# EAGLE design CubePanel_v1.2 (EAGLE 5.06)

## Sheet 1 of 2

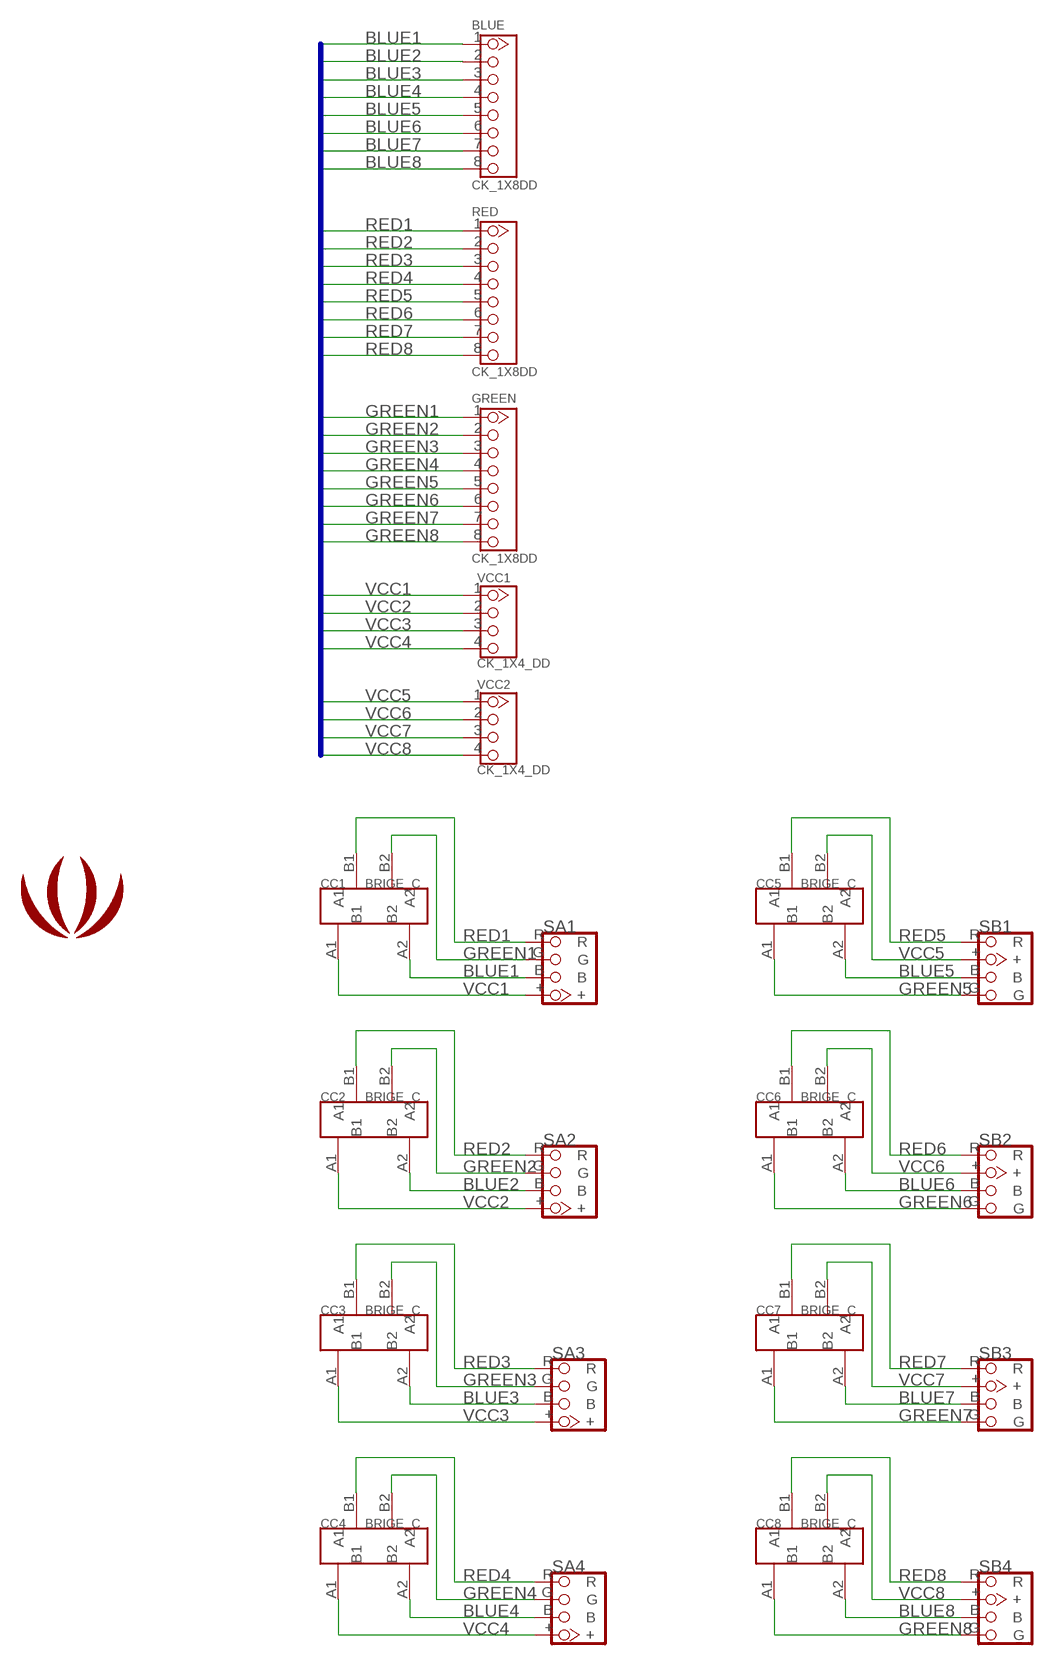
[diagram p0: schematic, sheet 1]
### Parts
BLUE  CK_1X8DD  [CK_1X8]
CC1  BRIGE_C  [BRIGE_C]
CC2  BRIGE_C  [BRIGE_C]
CC3  BRIGE_C  [BRIGE_C]
CC4  BRIGE_C  [BRIGE_C]
CC5  BRIGE_C  [BRIGE_C]
CC6  BRIGE_C  [BRIGE_C]
CC7  BRIGE_C  [BRIGE_C]
CC8  BRIGE_C  [BRIGE_C]
GREEN  CK_1X8DD  [CK_1X8]
LOGO1  LOGO_SILK  [LOGO_SILK]
RED  CK_1X8DD  [CK_1X8]
SA1  SIDE_A  [SIDE_A]
SA2  SIDE_A  [SIDE_A]
SA3  SIDE_A  [SIDE_A]
SA4  SIDE_A  [SIDE_A]
SB1  SIDE_B  [SIDE_B]
SB2  SIDE_B  [SIDE_B]
SB3  SIDE_B  [SIDE_B]
SB4  SIDE_B  [SIDE_B]
VCC1  CK_1X4_DD  [CK_1X4]
VCC2  CK_1X4_DD  [CK_1X4]

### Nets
BLUE1: BLUE.1 CC1.A2 SA1.B
BLUE2: BLUE.2 CC2.A2 SA2.B
BLUE3: BLUE.3 CC3.A2 SA3.B
BLUE4: BLUE.4 CC4.A2 SA4.B
BLUE5: BLUE.5 CC5.A2 SB1.B
BLUE6: BLUE.6 CC6.A2 SB2.B
BLUE7: BLUE.7 CC7.A2 SB3.B
BLUE8: BLUE.8 CC8.A2 SB4.B
GREEN1: CC1.B2 GREEN.1 SA1.G
GREEN2: CC2.B2 GREEN.2 SA2.G
GREEN3: CC3.B2 GREEN.3 SA3.G
GREEN4: CC4.B2 GREEN.4 SA4.G
GREEN5: CC5.A1 GREEN.5 SB1.G
GREEN6: CC6.A1 GREEN.6 SB2.G
GREEN7: CC7.A1 GREEN.7 SB3.G
GREEN8: CC8.A1 GREEN.8 SB4.G
RED1: CC1.B1 RED.1 SA1.R
RED2: CC2.B1 RED.2 SA2.R
RED3: CC3.B1 RED.3 SA3.R
RED4: CC4.B1 RED.4 SA4.R
RED5: CC5.B1 RED.5 SB1.R
RED6: CC6.B1 RED.6 SB2.R
RED7: CC7.B1 RED.7 SB3.R
RED8: CC8.B1 RED.8 SB4.R
VCC1: CC1.A1 SA1.+ VCC1.1
VCC2: CC2.A1 SA2.+ VCC1.2
VCC3: CC3.A1 SA3.+ VCC1.3
VCC4: CC4.A1 SA4.+ VCC1.4
VCC5: CC5.B2 SB1.+ VCC2.1
VCC6: CC6.B2 SB2.+ VCC2.2
VCC7: CC7.B2 SB3.+ VCC2.3
VCC8: CC8.B2 SB4.+ VCC2.4

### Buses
BLUE[1..8],RED[1..8],GREEN[1..8],VCC[1..8]

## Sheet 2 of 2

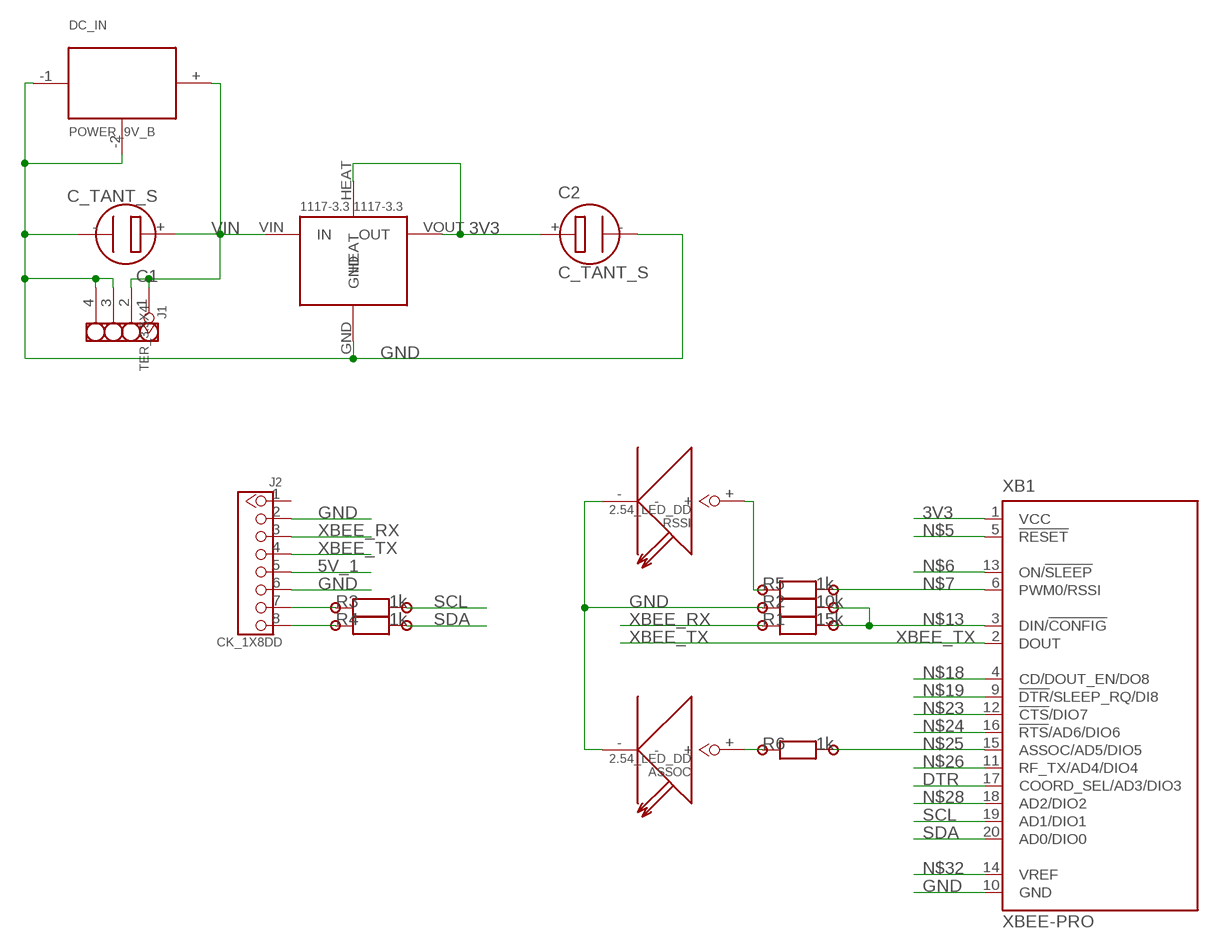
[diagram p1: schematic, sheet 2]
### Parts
1117-3.3  1117-3.3  LD1117TO220  [TO-220]
ASSOC  2.54_LED_DD  [2.54_LED]
C1  C_TANT_S  [C_TANT_S]
C2  C_TANT_S  [C_TANT_S]
DC_IN  POWER_9V_B  [POWER_9V_B]
J1  TER_3.5X4  [TER_3.5X4]
J2  CK_1X8DD  [CK_1X8]
R1  15k  R_350_25  [R_350_25]
R2  10k  R_350_25  [R_350_25]
R3  1k  R_350_25  [R_350_25]
R4  1k  R_350_25  [R_350_25]
R5  1k  R_350_25  [R_350_25]
R6  1k  R_350_25  [R_350_25]
RSSI  2.54_LED_DD  [2.54_LED]
XB1  XBEE-PRO  [XBEE-PRO]

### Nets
3V3: 1117-3.3.HEAT 1117-3.3.VOUT(OUT) C2.+ XB1.1(VCC)
5V_1: J2.5
DTR: XB1.17(COORD_SEL/AD3/DIO3)
GND: 1117-3.3.GND ASSOC.- C1.- C2.- DC_IN.-1 DC_IN.-2 J1.3 J1.4 J2.2 J2.6 R2.P$1 RSSI.- XB1.10(GND)
N$1: J2.7 R3.P$1
N$2: J2.8 R4.P$1
N$5: XB1.5(!RESET)
N$6: XB1.13(ON/!SLEEP)
N$7: R5.P$2 XB1.6(PWM0/RSSI)
N$13: R1.P$2 R2.P$2 XB1.3(DIN/!CONFIG)
N$18: XB1.4(CD/DOUT_EN/DO8)
N$19: XB1.9(!DTR!/SLEEP_RQ/DI8)
N$23: XB1.12(!CTS!/DIO7)
N$24: XB1.16(!RTS!/AD6/DIO6)
N$25: R6.P$2 XB1.15(ASSOC/AD5/DIO5)
N$26: XB1.11(RF_TX/AD4/DIO4)
N$28: XB1.18(AD2/DIO2)
N$32: XB1.14(VREF)
N$232: ASSOC.+ R6.P$1
N$239: R5.P$1 RSSI.+
SCL: R3.P$2 XB1.19(AD1/DIO1)
SDA: R4.P$2 XB1.20(AD0/DIO0)
VIN: 1117-3.3.VIN(IN) C1.+ DC_IN.+ J1.1 J1.2
XBEE_RX: J2.3 R1.P$1
XBEE_TX: J2.4 XB1.2(DOUT)
Unconnected: J2.1

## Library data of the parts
1117-3.3 = ICs_v54:LD1117
ASSOC RSSI = CPT_CJ:2.54_LED
BLUE GREEN J2 RED = CONNECTER:CK_1X8
C1 C2 = CPT_CJ:C_TANT_S
CC1-CC8 = CONNECTER:BRIGE
DC_IN = CONNECTER:POWER_9V_B
J1 = CONNECTER:TER_3.5X4
LOGO1 = logo:LOGO_SILK
R1-R6 = CPT_CJ:R_350_25
SA1-SA4 = Cube:SIDE_A
SB1-SB4 = Cube:SIDE_B
VCC1 VCC2 = CONNECTER:CK_1X4
XB1 = EXT_moudle:XBEE: XBee (TM) /XBee-PRO(TM) OEM RF Modules Source: MaxStream, Inc. xbee_productmanual.pdf

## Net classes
0 default: width 0.406 mm, drill 0.381 mm, clearance 0.254 mm
1 VCC1: width 0.813 mm, drill 0.381 mm, clearance 0.254 mm

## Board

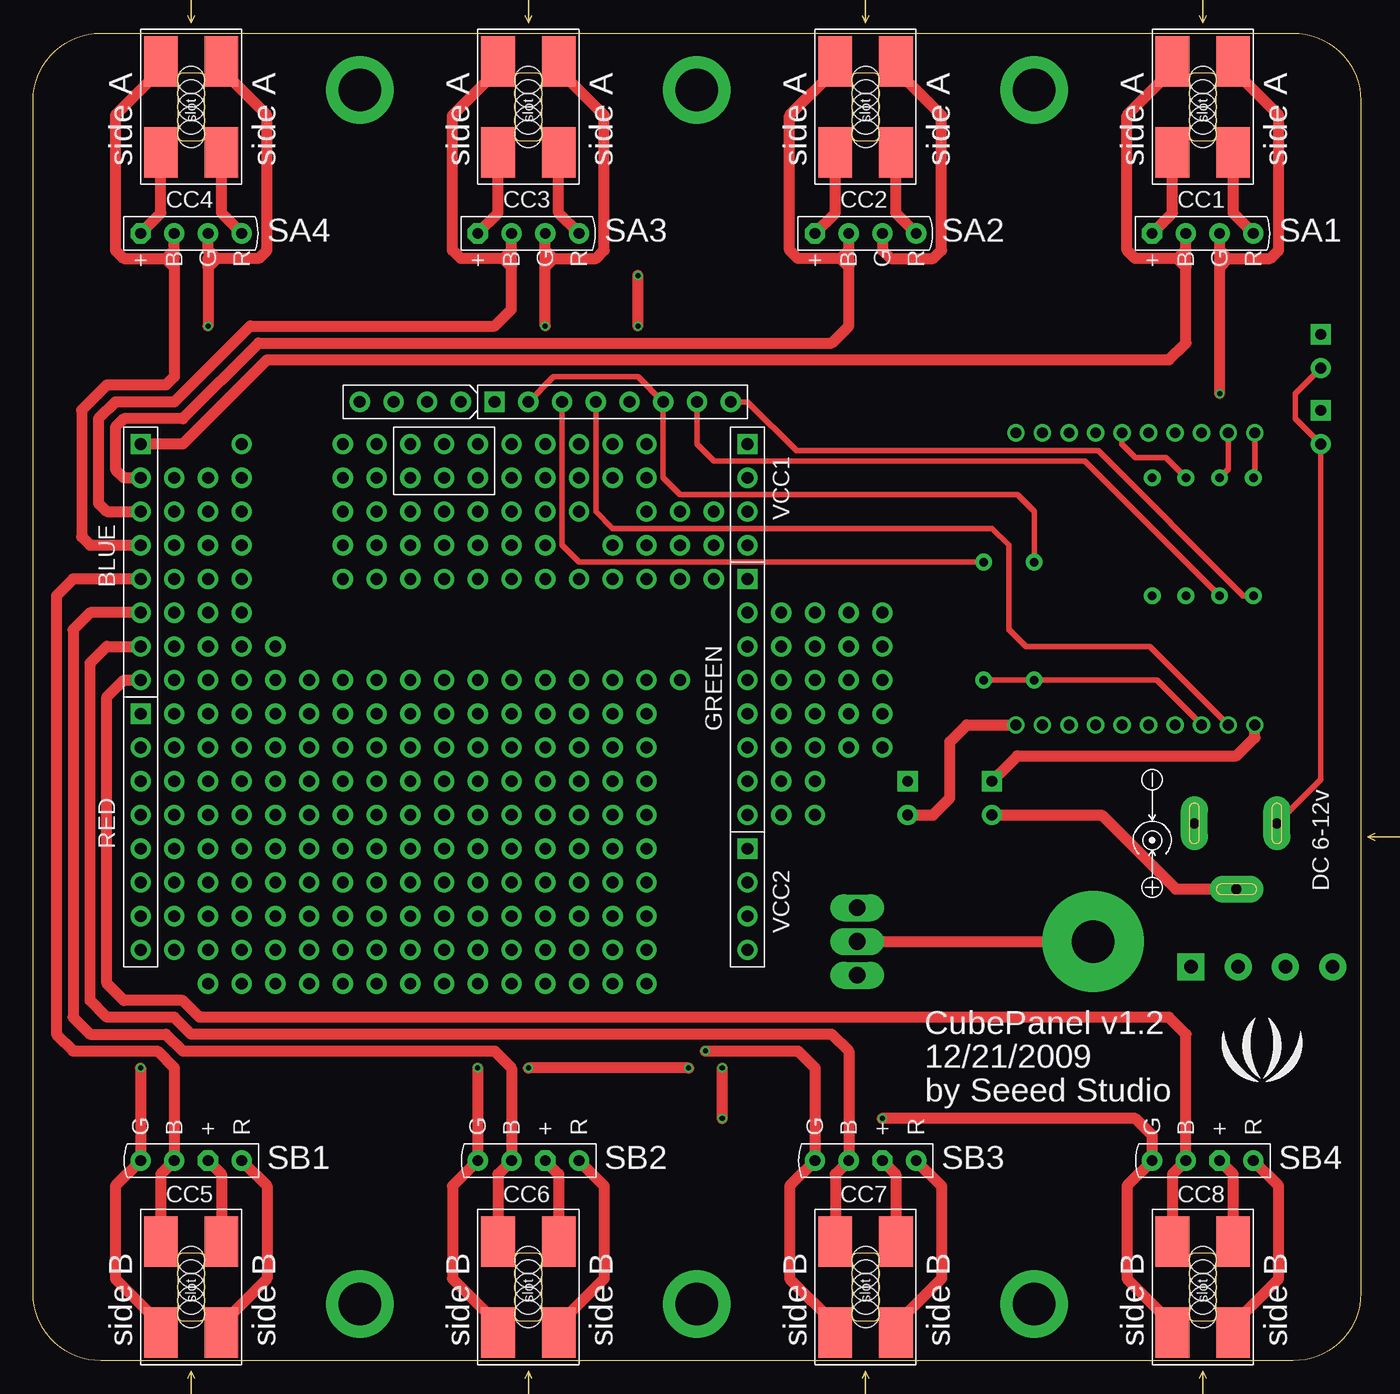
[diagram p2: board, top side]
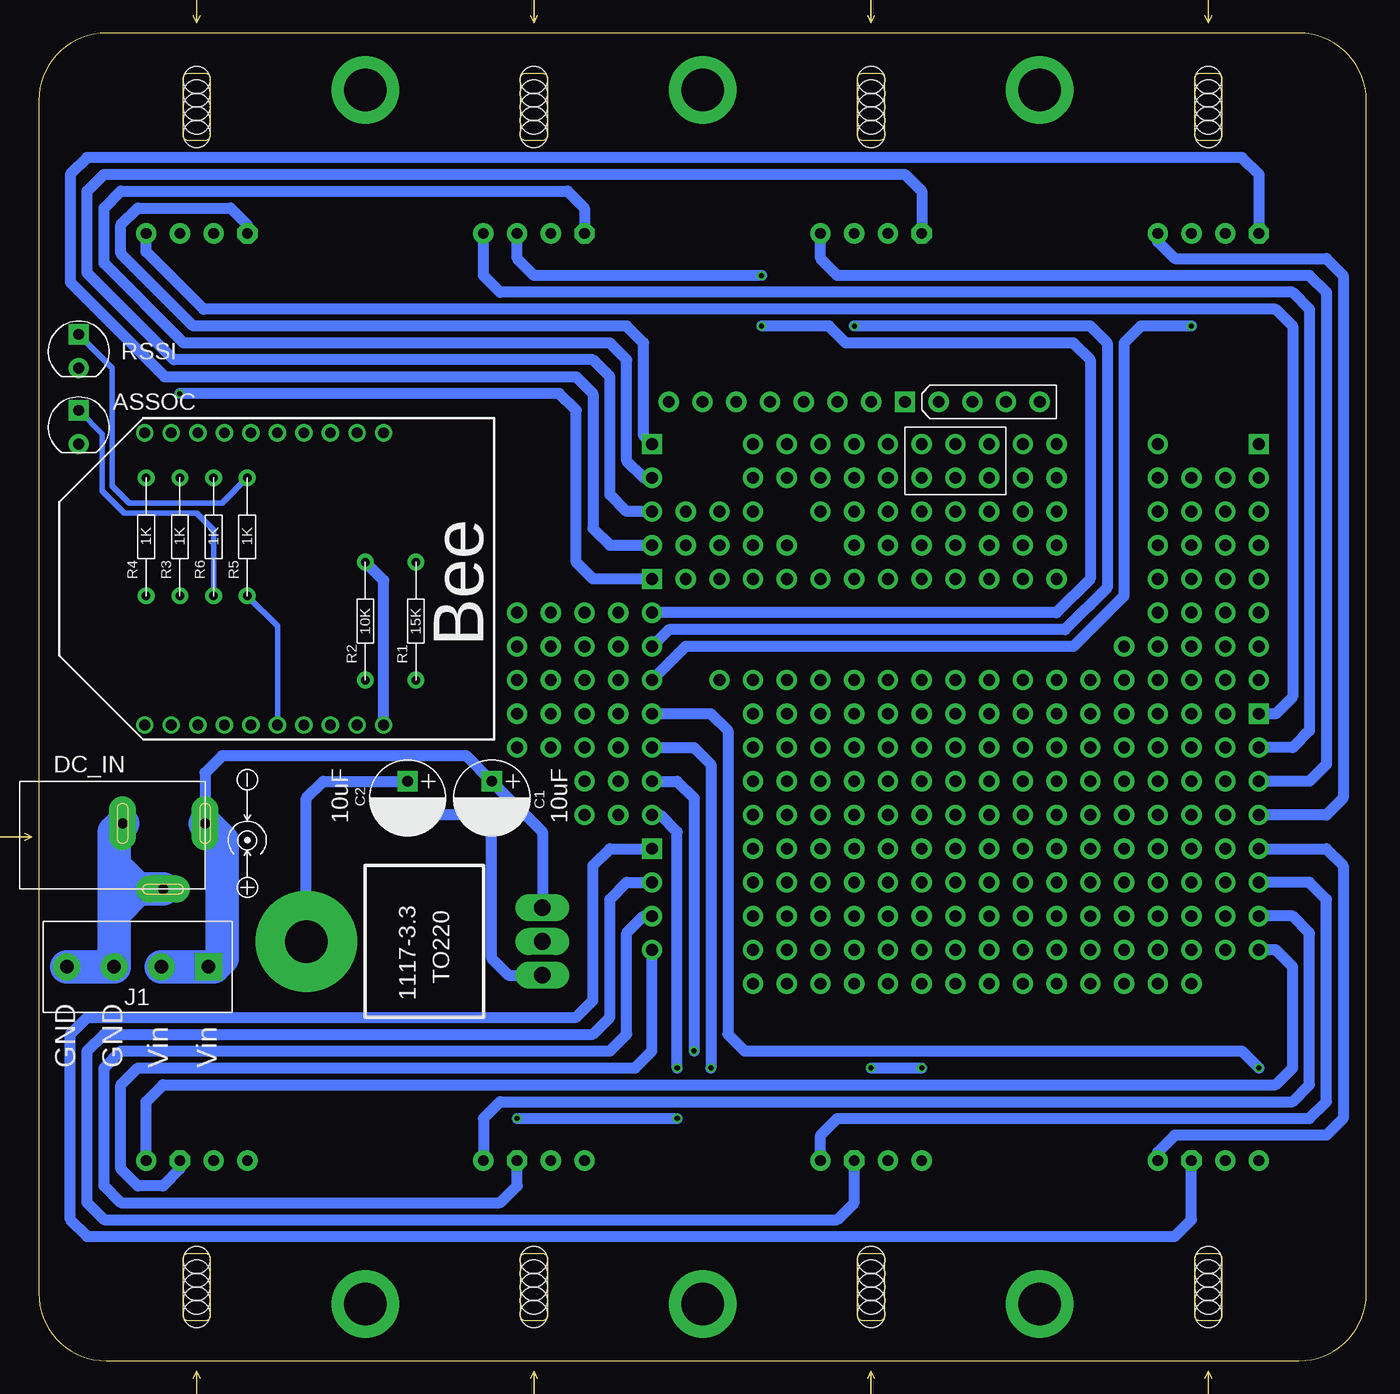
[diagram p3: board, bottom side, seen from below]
Size 100 x 100 mm. Coordinates in mm from the lower left corner, seen from the top.
Outline: 0,94.92 arc-90 5.08,100 94.92,100 arc-90 100,94.92 100,5.08 arc-90 94.92,0 5.08,0 arc-90 0,5.08 0,94.92
Copper layers (1*16): Top 0.035mm / dielectric 1.5mm / Bottom 0.035mm
Design rules "SeeedStudio_rule_no_angle_090911 *": minimum track width 6mil, minimum drill 12mil, track to track 6mil, track to pad 6mil, pad to pad 6mil, via to via 6mil, smd to smd 0mil, copper to edge 10mil, drill to drill 10mil, minimum pad ring 10mil, minimum via ring 6mil, stop-mask expansion 2mil, vias tented up to drill 25mil, thermal gap 10mil
Milling: 27 lines

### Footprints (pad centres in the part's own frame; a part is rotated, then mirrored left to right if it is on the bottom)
TO-220 = drill 1.27 pad 2.032 long: GND -2.54,-11.43; VIN 2.54,-11.43; VOUT 0,-11.43 | drill 3.2 pad 7.62 round: HEAT 0,6.35
2.54_LED = drill 0.813 pad 1.524 square: + -1.27,0 | drill 0.813 pad 1.524 round: - 1.27,0
CK_1X8 = drill 0.889 pad 1.524 square: 1 0,8.89 | drill 0.889 pad 1.524 round: 2 0,6.35; 3 0,3.81; 4 0,1.27; 5 0,-1.27; 6 0,-3.81; 7 0,-6.35; 8 0,-8.89
C_TANT_S = drill 0.813 pad 1.524 square: + -1.27,0 | drill 0.813 pad 1.524 round: - 1.27,0
BRIGE_C = smd 3.81 x 2.54: A1 -3.429,2.286; A2 3.429,2.286; B1 -3.429,-2.286; B2 3.429,-2.286 | hole 2.032: -2.032,0; 2.032,0; 0,0; -1.016,0; 1.016,0
POWER_9V_B = drill 0.762 pad 2.032 long: + 3.175,0; -1 -3.048,0; -2 0,-4.953
TER_3.5X4 = drill 1.016 pad 2.032 square: 1 0,5.334 | drill 1.016 pad 2.032 round: 2 0,1.778; 3 0,-1.778; 4 0,-5.334
R_350_25 = drill 0.635 pad 1.27 round: P$1 -4.445,0; P$2 4.445,0
SIDE_A = drill 0.813 pad 1.524 octagon: + -3.81,0 | drill 0.813 pad 1.524 round: B -1.27,0; G 1.27,0; R 3.81,0
SIDE_B = drill 0.813 pad 1.524 octagon: + -1.27,0 | drill 0.813 pad 1.524 round: B 1.27,0; G 3.81,0; R -3.81,0
CK_1X4 = drill 0.889 pad 1.524 square: 1 0,3.81 | drill 0.889 pad 1.524 round: 2 0,1.27; 3 0,-1.27; 4 0,-3.81
XBEE-PRO = drill 0.8 pad 1.27 round: 1 -11,9; 2 -11,7; 3 -11,5; 4 -11,3; 5 -11,1; 6 -11,-1; 7 -11,-3; 8 -11,-5; 9 -11,-7; 10 -11,-9; 11 11,-9; 12 11,-7; 13 11,-5; 14 11,-3; 15 11,-1; 16 11,1; 17 11,3; 18 11,5; 19 11,7; 20 11,9

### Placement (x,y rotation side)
1117-3.3  73.5,31.59 90 bottom
ASSOC  96.99,70.32 270 bottom
BLUE  8.09,60.16 0 top
C1  65.88,42.38 270 bottom
C2  72.22,42.38 270 bottom
CC1  88.1,94.45 90 top
CC2  62.7,94.45 90 top
CC3  37.3,94.45 90 top
CC4  11.9,94.45 90 top
CC5  11.9,5.55 90 top
CC6  37.3,5.55 90 top
CC7  62.7,5.55 90 top
CC8  88.1,5.55 90 top
DC_IN  90.64,40.48 0 bottom
GREEN  53.81,50 0 top
J1  92.55,29.68 270 bottom
J2  43.65,72.22 90 top
LOGO1  92.55,22.7 0 top
R1  71.59,55.72 270 bottom
R2  75.4,55.72 270 bottom
R3  89.37,62.06 90 bottom
R4  91.91,62.06 90 bottom
R5  84.29,62.06 270 bottom
R6  86.83,62.06 90 bottom
RED  8.09,39.84 0 top
RSSI  96.99,76.03 270 bottom
SA1  88.1,84.92 0 top
SA2  62.7,84.92 0 top
SA3  37.3,84.92 0 top
SA4  11.9,84.92 0 top
SB1  11.9,15.08 180 top
SB2  37.3,15.08 180 top
SB3  62.7,15.08 180 top
SB4  88.1,15.08 180 top
VCC1  53.81,65.24 0 top
VCC2  53.81,34.76 0 top
XB1  83.02,58.89 90 bottom

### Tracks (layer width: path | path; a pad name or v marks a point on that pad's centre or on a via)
3V3
  Top 0.813: C2.+ 74.13,45.55 90.64,45.55 92.02,46.94 XB1.1 | 1117-3.3.VOUT 1117-3.3.HEAT
  Bottom 0.813: 1117-3.3.HEAT 79.84,42.38 78.58,43.65 C2.+
BLUE1
  Top 0.813: 86.83,83.02 SA1.B | CC1.A2 85.81,97.24 82.38,93.81 82.38,83.66 83.02,83.02 86.19,83.02 | 86.83,83.02 86.83,83.66 86.19,83.02 | 86.83,83.02 86.19,83.02 | 86.83,83.02 86.83,82.38 86.19,83.02 | BLUE.1 11.27,69.05 17.62,75.4 85.56,75.4 86.83,76.67 86.83,83.02
BLUE2
  Top 0.813: 61.43,83.02 SA2.B | CC2.A2 60.41,97.24 56.98,93.81 56.98,83.66 57.62,83.02 60.8,83.02 | 61.43,83.02 61.43,83.66 60.8,83.02 | 61.43,83.02 60.8,83.02 | 61.43,83.02 61.43,82.38 60.8,83.02 | BLUE.2 6.82,66.51 6.19,67.14 6.19,70.32 6.82,70.95 11.27,70.95 16.98,76.67 60.16,76.67 61.43,77.94 61.43,83.02
BLUE3
  Top 0.813: 36.03,83.02 SA3.B | CC3.A2 35.01,97.24 31.59,93.81 31.59,83.66 32.22,83.02 35.39,83.02 | 35.39,83.02 36.03,82.38 36.03,83.02 | 36.03,83.02 35.39,83.02 | 35.39,83.02 36.03,83.66 36.03,83.02 | BLUE.3 5.55,63.97 4.91,64.61 4.91,70.95 6.19,72.22 10.63,72.22 16.34,77.94 34.76,77.94 36.03,79.21 36.03,83.02
BLUE4
  Top 0.813: 10.63,83.02 SA4.B | CC4.A2 9.61,97.24 6.19,93.81 6.19,83.66 6.82,83.02 9.99,83.02 | 9.99,83.02 10.63,82.38 | 10.63,82.38 10.63,83.02 | 9.99,83.02 10.63,83.02 | 9.99,83.02 10.63,83.66 10.63,83.02 | BLUE.4 4.28,61.43 3.65,62.06 3.65,71.59 5.55,73.5 9.99,73.5 10.63,74.13 10.63,82.38
BLUE5
  Top 0.813: CC5.A2 9.61,14.06 SB1.B 10.63,22.06 9.36,23.33 3.01,23.33 1.74,24.6 1.74,57.62 3.01,58.89 BLUE.5
BLUE6
  Top 0.813: CC6.A2 35.01,14.06 SB2.B 36.03,22.06 34.76,23.33 11.27,23.33 9.99,24.6 4.28,24.6 3.01,25.87 3.01,55.08 4.28,56.35 BLUE.6
BLUE7
  Top 0.813: CC7.A2 60.41,14.06 SB3.B 61.43,23.33 60.16,24.6 11.9,24.6 10.63,25.87 5.55,25.87 4.28,27.14 4.28,52.54 5.55,53.81 BLUE.7
BLUE8
  Top 0.813: CC8.A2 85.81,14.06 SB4.B 86.83,24.6 85.56,25.87 12.53,25.87 11.27,27.14 6.82,27.14 5.55,28.41 5.55,50 6.82,51.27 BLUE.8
GND
  Top 0.406: J2.2 39.2,74.13 45.55,74.13 J2.6 47.46,66.51 48.73,65.24 74.13,65.24 75.4,63.97 R2.P$1 | DC_IN.-1 96.99,43.78 ASSOC.- 95.09,70.95 95.09,72.86 RSSI.-
  Top 0.813: XB1.10 70.32,47.89 69.05,46.62 69.05,42.38 67.78,41.11 C1.- | C2.- 80.48,41.11 86.07,35.52 DC_IN.-2
  Bottom 0.813: C2.- C1.- 65.88,30.32 64.61,29.05 1117-3.3.GND | XB1.10 74.02,58.78 R2.P$1
  Bottom 2.54: J1.4 J1.3 94.32,35.52 | 94.32,35.52 94.32,39.84 DC_IN.-1 | DC_IN.-2 92.55,35.52 | 92.55,35.52 94.32,33.74 | 94.32,33.74 94.32,32.73 | 94.32,33.74 94.32,35.52 | 92.55,35.52 94.32,35.52 | 92.55,35.52 92.16,35.52 | 92.55,35.52 94.32,37.3 94.32,35.52
  pour Top: -15.41,81.75 -14.14,81.75 -14.14,80.48 -15.41,80.48
GREEN1  (via drill 0.38)
  Top 0.813: CC1.B2 90.39,97.24 93.81,93.81 93.81,83.66 93.18,83.02 90,83.02 | 90,83.02 89.37,83.02 89.37,82.38 90,83.02 | 89.37,83.66 90,83.02 | 89.37,83.66 SA1.G | v89.37,72.86 89.37,83.66
  Bottom 0.813: GREEN.1 58.26,58.89 59.52,60.16 59.52,71.59 60.8,72.86 v89.37,72.86
GREEN2  (via drill 0.38)
  Top 0.813: CC2.B2 64.99,97.24 68.41,93.81 68.41,83.66 67.78,83.02 64.61,83.02 63.97,83.66 SA2.G | v45.55,77.94 v45.55,81.75
  Bottom 0.813: v45.55,77.94 40.48,77.94 39.2,76.67 22.06,76.67 20.79,75.4 20.79,58.89 23.33,56.35 GREEN.2 | v45.55,81.75 62.7,81.75 63.97,83.02 SA2.G
GREEN3  (via drill 0.38)
  Top 0.813: CC3.B2 39.59,97.24 43.02,93.81 43.02,83.66 42.38,83.02 39.2,83.02 | 39.2,83.02 38.57,83.02 38.57,82.38 39.2,83.02 | 38.57,83.66 39.2,83.02 | 38.57,83.66 SA3.G | v38.57,77.94 38.57,83.66
  Bottom 0.813: v38.57,77.94 20.79,77.94 19.52,76.67 19.52,58.26 22.7,55.08 52.54,55.08 GREEN.3
GREEN4  (via drill 0.38)
  Top 0.813: CC4.B2 14.19,97.24 17.62,93.81 17.62,83.66 16.98,83.02 13.8,83.02 | 13.8,83.02 13.17,82.38 | 13.17,82.38 13.17,83.02 13.8,83.02 | 13.8,83.02 13.17,83.66 SA4.G | 13.17,82.38 v13.17,77.94
  Bottom 0.813: v13.17,77.94 16.98,77.94 18.25,76.67 18.25,57.62 22.06,53.81 51.27,53.81 GREEN.4
GREEN5  (via drill 0.38)
  Top 0.813: CC5.A1 9.61,2.76 6.19,6.19 6.19,13.17 SB1.G v8.09,22.06
  Bottom 0.813: GREEN.5 49.37,48.73 48.09,47.46 48.09,24.6 46.83,23.33 9.36,23.33 v8.09,22.06
GREEN6  (via drill 0.38)
  Top 0.813: CC6.A1 35.01,2.76 31.59,6.19 31.59,13.17 SB2.G v33.49,22.06 | v49.37,22.06 v37.3,22.06
  Bottom 0.813: GREEN.6 50.63,46.19 49.37,44.92 v49.37,22.06 | v37.3,22.06 v33.49,22.06
GREEN7  (via drill 0.38)
  Top 0.813: CC7.A1 60.41,2.76 56.98,6.19 56.98,13.17 SB3.G 58.89,22.06 57.62,23.33 v50.63,23.33
  Bottom 0.813: GREEN.7 51.91,43.65 50.63,42.38 v50.63,23.33
GREEN8  (via drill 0.38)
  Top 0.813: CC8.A1 85.81,2.76 82.38,6.19 82.38,13.17 SB4.G 84.29,16.98 83.02,18.25 v63.97,18.25 | v51.91,18.25 v51.91,22.06
  Bottom 0.813: v63.97,18.25 v51.91,18.25 | v51.91,22.06 51.91,39.84 53.17,41.11 GREEN.8
N$1
  Top 0.406: J2.7 50,69.05 51.27,67.78 79.21,67.78 R3.P$1
N$2
  Top 0.406: J2.8 53.81,72.22 57.49,68.54 80.23,68.54 91.15,57.62 R4.P$1
N$3  (via drill 0.89 pad 1.52)
  other vias: 10.63,66.51
N$4  (via drill 0.89 pad 1.52)
  other vias: 13.17,66.51
N$7
  Bottom 0.406: XB1.6 82.02,55.35 R5.P$2
N$13
  Top 0.406: R1.P$2 R2.P$2 84.64,51.27 XB1.3
N$15  (via drill 0.89 pad 1.52)
  other vias: 15.71,66.51
N$25
  Top 0.406: XB1.15 82.02,69.03 83.02,68.03 85.31,68.03 R6.P$2
N$27  (via drill 0.89 pad 1.52)
  other vias: 24.6,72.22
N$29  (via drill 0.89 pad 1.52)
  other vias: 27.14,72.22
N$31  (via drill 0.89 pad 1.52)
  other vias: 29.68,72.22
N$33  (via drill 0.89 pad 1.52)
  other vias: 32.22,72.22
N$35  (via drill 0.89 pad 1.52)
  other vias: 30.95,69.05
N$36  (via drill 0.89 pad 1.52)
  other vias: 28.41,69.05
N$37  (via drill 0.89 pad 1.52)
  other vias: 28.41,66.51
N$38  (via drill 0.89 pad 1.52)
  other vias: 30.95,66.51
N$39  (via drill 0.89 pad 1.52)
  other vias: 15.71,63.97
N$40  (via drill 0.89 pad 1.52)
  other vias: 13.17,63.97
N$41  (via drill 0.89 pad 1.52)
  other vias: 10.63,63.97
N$42  (via drill 0.89 pad 1.52)
  other vias: 10.63,61.43
N$43  (via drill 0.89 pad 1.52)
  other vias: 13.17,61.43
N$44  (via drill 0.89 pad 1.52)
  other vias: 15.71,61.43
N$45  (via drill 0.89 pad 1.52)
  other vias: 25.87,69.05
N$47  (via drill 0.89 pad 1.52)
  other vias: 23.33,69.05
N$48  (via drill 0.89 pad 1.52)
  other vias: 23.33,66.51
N$49  (via drill 0.89 pad 1.52)
  other vias: 25.87,66.51
N$50  (via drill 0.89 pad 1.52)
  other vias: 10.63,58.89
N$52  (via drill 0.89 pad 1.52)
  other vias: 13.17,58.89
N$53  (via drill 0.89 pad 1.52)
  other vias: 15.71,58.89
N$54  (via drill 0.89 pad 1.52)
  other vias: 25.87,63.97
N$55  (via drill 0.89 pad 1.52)
  other vias: 23.33,63.97
N$56  (via drill 0.89 pad 1.52)
  other vias: 28.41,63.97
N$57  (via drill 0.89 pad 1.52)
  other vias: 30.95,63.97
N$58  (via drill 0.89 pad 1.52)
  other vias: 30.95,61.43
N$59  (via drill 0.89 pad 1.52)
  other vias: 28.41,61.43
N$60  (via drill 0.89 pad 1.52)
  other vias: 25.87,61.43
N$61  (via drill 0.89 pad 1.52)
  other vias: 23.33,61.43
N$62  (via drill 0.89 pad 1.52)
  other vias: 15.71,56.35
N$63  (via drill 0.89 pad 1.52)
  other vias: 13.17,56.35
N$64  (via drill 0.89 pad 1.52)
  other vias: 10.63,56.35
N$65  (via drill 0.89 pad 1.52)
  other vias: 10.63,53.81
N$66  (via drill 0.89 pad 1.52)
  other vias: 13.17,53.81
N$67  (via drill 0.89 pad 1.52)
  other vias: 15.71,53.81
N$68  (via drill 0.89 pad 1.52)
  other vias: 23.33,58.89
N$69  (via drill 0.89 pad 1.52)
  other vias: 25.87,58.89
N$70  (via drill 0.89 pad 1.52)
  other vias: 28.41,58.89
N$71  (via drill 0.89 pad 1.52)
  other vias: 30.95,58.89
N$72  (via drill 0.89 pad 1.52)
  other vias: 38.57,69.05
N$73  (via drill 0.89 pad 1.52)
  other vias: 38.57,66.51
N$74  (via drill 0.89 pad 1.52)
  other vias: 38.57,63.97
N$75  (via drill 0.89 pad 1.52)
  other vias: 38.57,61.43
N$76  (via drill 0.89 pad 1.52)
  other vias: 15.71,51.27
N$77  (via drill 0.89 pad 1.52)
  other vias: 13.17,51.27
N$78  (via drill 0.89 pad 1.52)
  other vias: 10.63,51.27
N$79  (via drill 0.89 pad 1.52)
  other vias: 10.63,48.73
N$80  (via drill 0.89 pad 1.52)
  other vias: 13.17,48.73
N$81  (via drill 0.89 pad 1.52)
  other vias: 15.71,48.73
N$82  (via drill 0.89 pad 1.52)
  other vias: 18.25,48.73
N$83  (via drill 0.89 pad 1.52)
  other vias: 20.79,48.73
N$84  (via drill 0.89 pad 1.52)
  other vias: 23.33,48.73
N$85  (via drill 0.89 pad 1.52)
  other vias: 25.87,48.73
N$86  (via drill 0.89 pad 1.52)
  other vias: 25.87,46.19
N$87  (via drill 0.89 pad 1.52)
  other vias: 23.33,46.19
N$88  (via drill 0.89 pad 1.52)
  other vias: 20.79,46.19
N$89  (via drill 0.89 pad 1.52)
  other vias: 18.25,46.19
N$90  (via drill 0.89 pad 1.52)
  other vias: 15.71,46.19
N$91  (via drill 0.89 pad 1.52)
  other vias: 13.17,46.19
N$92  (via drill 0.89 pad 1.52)
  other vias: 10.63,46.19
N$93  (via drill 0.89 pad 1.52)
  other vias: 10.63,43.65
N$94  (via drill 0.89 pad 1.52)
  other vias: 13.17,43.65
N$95  (via drill 0.89 pad 1.52)
  other vias: 15.71,43.65
N$96  (via drill 0.89 pad 1.52)
  other vias: 18.25,43.65
N$97  (via drill 0.89 pad 1.52)
  other vias: 20.79,43.65
N$98  (via drill 0.89 pad 1.52)
  other vias: 23.33,43.65
N$99  (via drill 0.89 pad 1.52)
  other vias: 25.87,43.65
N$100  (via drill 0.89 pad 1.52)
  other vias: 28.41,48.73
N$101  (via drill 0.89 pad 1.52)
  other vias: 30.95,48.73
N$102  (via drill 0.89 pad 1.52)
  other vias: 33.49,48.73
N$103  (via drill 0.89 pad 1.52)
  other vias: 36.03,48.73
N$104  (via drill 0.89 pad 1.52)
  other vias: 38.57,48.73
N$105  (via drill 0.89 pad 1.52)
  other vias: 41.11,48.73
N$106  (via drill 0.89 pad 1.52)
  other vias: 43.65,48.73
N$107  (via drill 0.89 pad 1.52)
  other vias: 46.19,48.73
N$108  (via drill 0.89 pad 1.52)
  other vias: 46.19,46.19
N$109  (via drill 0.89 pad 1.52)
  other vias: 43.65,46.19
N$110  (via drill 0.89 pad 1.52)
  other vias: 41.11,46.19
N$111  (via drill 0.89 pad 1.52)
  other vias: 38.57,46.19
N$112  (via drill 0.89 pad 1.52)
  other vias: 36.03,46.19
N$113  (via drill 0.89 pad 1.52)
  other vias: 33.49,46.19
N$114  (via drill 0.89 pad 1.52)
  other vias: 30.95,46.19
N$115  (via drill 0.89 pad 1.52)
  other vias: 28.41,46.19
N$116  (via drill 0.89 pad 1.52)
  other vias: 28.41,43.65
N$117  (via drill 0.89 pad 1.52)
  other vias: 30.95,43.65
N$118  (via drill 0.89 pad 1.52)
  other vias: 33.49,43.65
N$119  (via drill 0.89 pad 1.52)
  other vias: 36.03,43.65
N$120  (via drill 0.89 pad 1.52)
  other vias: 38.57,43.65
N$121  (via drill 0.89 pad 1.52)
  other vias: 41.11,43.65
N$122  (via drill 0.89 pad 1.52)
  other vias: 43.65,43.65
N$123  (via drill 0.89 pad 1.52)
  other vias: 46.19,43.65
N$124  (via drill 0.89 pad 1.52)
  other vias: 46.19,41.11
N$125  (via drill 0.89 pad 1.52)
  other vias: 43.65,41.11
N$126  (via drill 0.89 pad 1.52)
  other vias: 41.11,41.11
N$127  (via drill 0.89 pad 1.52)
  other vias: 38.57,41.11
N$128  (via drill 0.89 pad 1.52)
  other vias: 36.03,41.11
N$129  (via drill 0.89 pad 1.52)
  other vias: 33.49,41.11
N$130  (via drill 0.89 pad 1.52)
  other vias: 30.95,41.11
N$131  (via drill 0.89 pad 1.52)
  other vias: 28.41,41.11
N$132  (via drill 0.89 pad 1.52)
  other vias: 25.87,41.11
N$133  (via drill 0.89 pad 1.52)
  other vias: 23.33,41.11
N$134  (via drill 0.89 pad 1.52)
  other vias: 20.79,41.11
N$135  (via drill 0.89 pad 1.52)
  other vias: 18.25,41.11
N$136  (via drill 0.89 pad 1.52)
  other vias: 15.71,41.11
N$137  (via drill 0.89 pad 1.52)
  other vias: 13.17,41.11
N$138  (via drill 0.89 pad 1.52)
  other vias: 10.63,41.11
N$139  (via drill 0.89 pad 1.52)
  other vias: 10.63,38.57
N$140  (via drill 0.89 pad 1.52)
  other vias: 13.17,38.57
N$141  (via drill 0.89 pad 1.52)
  other vias: 15.71,38.57
N$142  (via drill 0.89 pad 1.52)
  other vias: 18.25,38.57
N$143  (via drill 0.89 pad 1.52)
  other vias: 20.79,38.57
N$144  (via drill 0.89 pad 1.52)
  other vias: 23.33,38.57
N$145  (via drill 0.89 pad 1.52)
  other vias: 25.87,38.57
N$146  (via drill 0.89 pad 1.52)
  other vias: 28.41,38.57
N$147  (via drill 0.89 pad 1.52)
  other vias: 30.95,38.57
N$148  (via drill 0.89 pad 1.52)
  other vias: 33.49,38.57
N$149  (via drill 0.89 pad 1.52)
  other vias: 36.03,38.57
N$150  (via drill 0.89 pad 1.52)
  other vias: 38.57,38.57
N$151  (via drill 0.89 pad 1.52)
  other vias: 41.11,38.57
N$152  (via drill 0.89 pad 1.52)
  other vias: 43.65,38.57
N$153  (via drill 0.89 pad 1.52)
  other vias: 46.19,38.57
N$154  (via drill 0.89 pad 1.52)
  other vias: 46.19,36.03
N$155  (via drill 0.89 pad 1.52)
  other vias: 43.65,36.03
N$156  (via drill 0.89 pad 1.52)
  other vias: 41.11,36.03
N$157  (via drill 0.89 pad 1.52)
  other vias: 38.57,36.03
N$158  (via drill 0.89 pad 1.52)
  other vias: 36.03,36.03
N$159  (via drill 0.89 pad 1.52)
  other vias: 33.49,36.03
N$160  (via drill 0.89 pad 1.52)
  other vias: 30.95,36.03
N$161  (via drill 0.89 pad 1.52)
  other vias: 28.41,36.03
N$162  (via drill 0.89 pad 1.52)
  other vias: 25.87,36.03
N$163  (via drill 0.89 pad 1.52)
  other vias: 23.33,36.03
N$164  (via drill 0.89 pad 1.52)
  other vias: 20.79,36.03
N$165  (via drill 0.89 pad 1.52)
  other vias: 18.25,36.03
N$166  (via drill 0.89 pad 1.52)
  other vias: 15.71,36.03
N$167  (via drill 0.89 pad 1.52)
  other vias: 13.17,36.03
N$168  (via drill 0.89 pad 1.52)
  other vias: 10.63,36.03
N$169  (via drill 0.89 pad 1.52)
  other vias: 10.63,33.49
N$170  (via drill 0.89 pad 1.52)
  other vias: 13.17,33.49
N$171  (via drill 0.89 pad 1.52)
  other vias: 15.71,33.49
N$172  (via drill 0.89 pad 1.52)
  other vias: 18.25,33.49
N$173  (via drill 0.89 pad 1.52)
  other vias: 20.79,33.49
N$174  (via drill 0.89 pad 1.52)
  other vias: 23.33,33.49
N$175  (via drill 0.89 pad 1.52)
  other vias: 25.87,33.49
N$176  (via drill 0.89 pad 1.52)
  other vias: 28.41,33.49
N$177  (via drill 0.89 pad 1.52)
  other vias: 30.95,33.49
N$178  (via drill 0.89 pad 1.52)
  other vias: 33.49,33.49
N$179  (via drill 0.89 pad 1.52)
  other vias: 36.03,33.49
N$180  (via drill 0.89 pad 1.52)
  other vias: 38.57,33.49
N$181  (via drill 0.89 pad 1.52)
  other vias: 41.11,33.49
N$182  (via drill 0.89 pad 1.52)
  other vias: 43.65,33.49
N$183  (via drill 0.89 pad 1.52)
  other vias: 46.19,33.49
N$184  (via drill 0.89 pad 1.52)
  other vias: 46.19,30.95
N$185  (via drill 0.89 pad 1.52)
  other vias: 43.65,30.95
N$186  (via drill 0.89 pad 1.52)
  other vias: 41.11,30.95
N$187  (via drill 0.89 pad 1.52)
  other vias: 38.57,30.95
N$188  (via drill 0.89 pad 1.52)
  other vias: 36.03,30.95
N$189  (via drill 0.89 pad 1.52)
  other vias: 33.49,30.95
N$190  (via drill 0.89 pad 1.52)
  other vias: 30.95,30.95
N$191  (via drill 0.89 pad 1.52)
  other vias: 28.41,30.95
N$192  (via drill 0.89 pad 1.52)
  other vias: 25.87,30.95
N$193  (via drill 0.89 pad 1.52)
  other vias: 23.33,30.95
N$194  (via drill 0.89 pad 1.52)
  other vias: 20.79,30.95
N$195  (via drill 0.89 pad 1.52)
  other vias: 18.25,30.95
N$196  (via drill 0.89 pad 1.52)
  other vias: 15.71,30.95
N$197  (via drill 0.89 pad 1.52)
  other vias: 13.17,30.95
N$198  (via drill 0.89 pad 1.52)
  other vias: 10.63,30.95
N$199  (via drill 0.89 pad 1.52)
  other vias: 41.11,28.41
N$200  (via drill 0.89 pad 1.52)
  other vias: 43.65,28.41
N$201  (via drill 0.89 pad 1.52)
  other vias: 46.19,28.41
N$202  (via drill 0.89 pad 1.52)
  other vias: 33.49,58.89
N$203  (via drill 0.89 pad 1.52)
  other vias: 33.49,61.43
N$204  (via drill 0.89 pad 1.52)
  other vias: 33.49,63.97
N$205  (via drill 0.89 pad 1.52)
  other vias: 33.49,66.51
N$206  (via drill 0.89 pad 1.52)
  other vias: 33.49,69.05
N$207  (via drill 0.89 pad 1.52)
  other vias: 36.03,69.05
N$208  (via drill 0.89 pad 1.52)
  other vias: 36.03,66.51
N$209  (via drill 0.89 pad 1.52)
  other vias: 36.03,63.97
N$210  (via drill 0.89 pad 1.52)
  other vias: 36.03,61.43
N$211  (via drill 0.89 pad 1.52)
  other vias: 36.03,58.89
N$212  (via drill 0.89 pad 1.52)
  other vias: 56.35,56.35
N$213  (via drill 0.89 pad 1.52)
  other vias: 58.89,56.35
N$214  (via drill 0.89 pad 1.52)
  other vias: 61.43,56.35
N$215  (via drill 0.89 pad 1.52)
  other vias: 63.97,56.35
N$216  (via drill 0.89 pad 1.52)
  other vias: 63.97,53.81
N$217  (via drill 0.89 pad 1.52)
  other vias: 61.43,53.81
N$218  (via drill 0.89 pad 1.52)
  other vias: 58.89,53.81
N$219  (via drill 0.89 pad 1.52)
  other vias: 56.35,53.81
N$220  (via drill 0.89 pad 1.52)
  other vias: 56.35,51.27
N$221  (via drill 0.89 pad 1.52)
  other vias: 58.89,51.27
N$222  (via drill 0.89 pad 1.52)
  other vias: 61.43,51.27
N$223  (via drill 0.89 pad 1.52)
  other vias: 63.97,51.27
N$224  (via drill 0.89 pad 1.52)
  other vias: 63.97,48.73
N$225  (via drill 0.89 pad 1.52)
  other vias: 61.43,48.73
N$226  (via drill 0.89 pad 1.52)
  other vias: 58.89,48.73
N$227  (via drill 0.89 pad 1.52)
  other vias: 56.35,48.73
N$228  (via drill 0.89 pad 1.52)
  other vias: 56.35,46.19
N$229  (via drill 0.89 pad 1.52)
  other vias: 58.89,46.19
N$230  (via drill 0.89 pad 1.52)
  other vias: 61.43,46.19
N$231  (via drill 0.89 pad 1.52)
  other vias: 63.97,46.19
N$232
  Bottom 0.406: R6.P$1 86.83,62.57 88.1,63.84 93.56,63.84 95.21,65.49 95.21,69.81 ASSOC.+
N$233  (via drill 0.89 pad 1.52)
  other vias: 58.89,43.65
N$234  (via drill 0.89 pad 1.52)
  other vias: 56.35,43.65
N$235  (via drill 0.89 pad 1.52)
  other vias: 56.35,41.11
N$236  (via drill 0.89 pad 1.52)
  other vias: 58.89,41.11
N$237  (via drill 0.89 pad 1.52)
  other vias: 15.71,69.05
N$238  (via drill 0.89 pad 1.52)
  other vias: 18.25,53.81
N$239
  Bottom 0.406: R5.P$1 86.19,64.61 93.18,64.61 94.45,65.88 94.45,74.77 RSSI.+
N$243  (via drill 0.89 pad 1.52)
  other vias: 38.57,58.89
N$244  (via drill 3.2 pad 5.08)
  other vias: 24.6,95.72
N$245  (via drill 3.2 pad 5.08)
  other vias: 50,95.72
N$246  (via drill 3.2 pad 5.08)
  other vias: 75.4,95.72
N$247  (via drill 3.2 pad 5.08)
  other vias: 24.6,4.28
N$248  (via drill 3.2 pad 5.08)
  other vias: 50,4.28
N$249  (via drill 3.2 pad 5.08)
  other vias: 75.4,4.28
N$250  (via drill 0.89 pad 1.52)
  other vias: 41.11,58.89
N$251  (via drill 0.89 pad 1.52)
  other vias: 43.65,58.89
N$252  (via drill 0.89 pad 1.52)
  other vias: 46.19,58.89
N$253  (via drill 0.89 pad 1.52)
  other vias: 48.73,58.89
N$254  (via drill 0.89 pad 1.52)
  other vias: 51.27,58.89
N$255  (via drill 0.89 pad 1.52)
  other vias: 41.11,69.05
N$256  (via drill 0.89 pad 1.52)
  other vias: 41.11,66.51
N$257  (via drill 0.89 pad 1.52)
  other vias: 41.11,63.97
N$258  (via drill 0.89 pad 1.52)
  other vias: 43.65,61.43
N$259  (via drill 0.89 pad 1.52)
  other vias: 46.19,61.43
N$260  (via drill 0.89 pad 1.52)
  other vias: 48.73,61.43
N$261  (via drill 0.89 pad 1.52)
  other vias: 51.27,61.43
N$262  (via drill 0.89 pad 1.52)
  other vias: 51.27,63.97
N$263  (via drill 0.89 pad 1.52)
  other vias: 48.73,63.97
N$264  (via drill 0.89 pad 1.52)
  other vias: 46.19,63.97
N$265  (via drill 0.89 pad 1.52)
  other vias: 46.19,66.51
N$266  (via drill 0.89 pad 1.52)
  other vias: 46.19,69.05
N$267  (via drill 0.89 pad 1.52)
  other vias: 43.65,69.05
N$268  (via drill 0.89 pad 1.52)
  other vias: 43.65,66.51
N$269  (via drill 0.89 pad 1.52)
  other vias: 18.25,51.27
N$270  (via drill 0.89 pad 1.52)
  other vias: 20.79,51.27
N$271  (via drill 0.89 pad 1.52)
  other vias: 23.33,51.27
N$272  (via drill 0.89 pad 1.52)
  other vias: 25.87,51.27
N$273  (via drill 0.89 pad 1.52)
  other vias: 28.41,51.27
N$274  (via drill 0.89 pad 1.52)
  other vias: 30.95,51.27
N$275  (via drill 0.89 pad 1.52)
  other vias: 33.49,51.27
N$276  (via drill 0.89 pad 1.52)
  other vias: 36.03,51.27
N$277  (via drill 0.89 pad 1.52)
  other vias: 38.57,51.27
N$278  (via drill 0.89 pad 1.52)
  other vias: 41.11,51.27
N$279  (via drill 0.89 pad 1.52)
  other vias: 43.65,51.27
N$280  (via drill 0.89 pad 1.52)
  other vias: 46.19,51.27
N$281  (via drill 0.89 pad 1.52)
  other vias: 48.73,51.27
N$282  (via drill 0.89 pad 1.52)
  other vias: 13.17,28.41
N$283  (via drill 0.89 pad 1.52)
  other vias: 15.71,28.41
N$284  (via drill 0.89 pad 1.52)
  other vias: 18.25,28.41
N$285  (via drill 0.89 pad 1.52)
  other vias: 20.79,28.41
N$286  (via drill 0.89 pad 1.52)
  other vias: 23.33,28.41
N$287  (via drill 0.89 pad 1.52)
  other vias: 25.87,28.41
N$288  (via drill 0.89 pad 1.52)
  other vias: 28.41,28.41
N$289  (via drill 0.89 pad 1.52)
  other vias: 30.95,28.41
N$290  (via drill 0.89 pad 1.52)
  other vias: 33.49,28.41
N$291  (via drill 0.89 pad 1.52)
  other vias: 36.03,28.41
N$292  (via drill 0.89 pad 1.52)
  other vias: 38.57,28.41
RED1
  Top 0.813: CC1.B1 90.39,86.45 SA1.R
  Bottom 0.813: RED.1 6.82,48.73 5.55,50 5.55,77.94 6.82,79.21 87.59,79.21 91.91,83.53 SA1.R
RED2
  Top 0.813: CC2.B1 64.99,86.45 SA2.R
  Bottom 0.813: RED.2 5.55,46.19 4.28,47.46 4.28,79.21 5.55,80.48 65.24,80.48 66.51,81.75 SA2.R
RED3
  Top 0.813: CC3.B1 39.59,86.45 SA3.R
  Bottom 0.813: RED.3 4.28,43.65 3.01,44.92 3.01,80.48 4.28,81.75 39.84,81.75 41.11,83.02 SA3.R
RED4
  Top 0.813: CC4.B1 14.19,86.45 SA4.R
  Bottom 0.813: RED.4 3.01,41.11 1.74,42.38 1.74,81.75 3.01,83.02 14.44,83.02 15.71,84.29 SA4.R
RED5
  Top 0.813: CC5.B1 14.19,2.76 17.62,6.19 17.62,13.17 SB1.R
  Bottom 0.813: RED.5 3.01,38.57 1.74,37.3 1.74,18.25 3.01,16.98 14.44,16.98 15.71,15.71 SB1.R
RED6
  Top 0.813: CC6.B1 39.59,2.76 43.02,6.19 43.02,13.17 SB2.R
  Bottom 0.813: RED.6 4.28,36.03 3.01,34.76 3.01,19.52 4.28,18.25 39.84,18.25 41.11,16.98 SB2.R
RED7
  Top 0.813: CC7.B1 64.99,2.76 68.41,6.19 68.41,13.17 SB3.R
  Bottom 0.813: RED.7 5.55,33.49 4.28,32.22 4.28,20.79 5.55,19.52 65.24,19.52 66.51,18.25 SB3.R
RED8
  Top 0.813: CC8.B1 90.39,2.76 93.81,6.19 93.81,13.17 SB4.R
  Bottom 0.813: RED.8 6.82,30.95 5.55,29.68 5.55,22.06 6.82,20.79 90.64,20.79 91.91,19.52 SB4.R
SCL
  Top 0.406: XB1.19 90.02,67.16 R3.P$2
SDA
  Top 0.406: XB1.20 92.02,66.62 R4.P$2
VCC1
  Top 0.813: CC1.A1 85.81,86.45 SA1.+
  Bottom 0.813: VCC1.1 54.45,69.69 54.45,76.67 55.72,77.94 88.35,77.94 93.81,83.4 93.81,85.56 92.55,86.83 85.56,86.83 84.29,85.56 SA1.+
VCC2
  Top 0.813: CC2.A1 60.41,86.45 SA2.+
  Bottom 0.813: VCC1.2 54.45,66.51 55.72,67.78 55.72,75.4 56.98,76.67 89.09,76.67 95.09,82.66 95.09,86.83 93.81,88.1 60.16,88.1 58.89,86.83 SA2.+
VCC3
  Top 0.813: CC3.A1 35.01,86.45 SA3.+
  Bottom 0.813: VCC1.3 55.72,63.97 56.98,65.24 56.98,74.13 58.26,75.4 89.82,75.4 96.35,81.94 96.35,88.1 95.09,89.37 34.76,89.37 33.49,88.1 SA3.+
VCC4
  Top 0.813: CC4.A1 9.61,86.45 SA4.+
  Bottom 0.813: VCC1.4 56.98,61.43 58.26,62.7 58.26,72.86 59.52,74.13 90.53,74.13 97.62,81.23 97.62,89.37 96.35,90.64 9.36,90.64 8.09,89.37 SA4.+
VCC5
  Top 0.813: CC5.B2 14.19,14.06 SB1.+
  Bottom 0.813: VCC2.1 56.98,38.57 58.26,37.3 58.26,27.14 59.52,25.87 96.35,25.87 97.62,24.6 97.62,10.63 96.35,9.36 14.44,9.36 13.17,10.63 SB1.+
VCC6
  Top 0.813: CC6.B2 39.59,14.06 SB2.+
  Bottom 0.813: VCC2.2 55.72,36.03 56.98,34.76 56.98,25.87 58.26,24.6 95.09,24.6 96.35,23.33 96.35,11.9 95.09,10.63 39.84,10.63 38.57,11.9 SB2.+
VCC7
  Top 0.813: CC7.B2 64.99,14.06 SB3.+
  Bottom 0.813: VCC2.3 54.45,33.49 55.72,32.22 55.72,24.6 56.98,23.33 93.81,23.33 95.09,22.06 95.09,13.17 93.81,11.9 65.24,11.9 63.97,13.17 SB3.+
VCC8
  Top 0.813: CC8.B2 90.39,14.06 SB4.+
  Bottom 0.813: VCC2.4 53.81,23.33 55.08,22.06 92.55,22.06 93.81,20.79 93.81,14.44 92.55,13.17 90.64,13.17 89.37,14.44 SB4.+
VIN
  Bottom 0.813: DC_IN.+ 87.47,44.28 86.19,45.55 67.78,45.55 C1.+ 62.06,39.84 1117-3.3.VIN
  Bottom 2.54: J1.2 J1.1 86.83,29.68 86.19,30.32 86.19,39.2 DC_IN.+
XBEE_RX
  Top 0.406: J2.3 39.84,61.43 41.11,60.16 R1.P$1
XBEE_TX
  Top 0.406: J2.4 42.38,63.97 43.65,62.7 72.22,62.7 73.5,61.43 73.5,55.08 74.77,53.81 84.1,53.81 XB1.2

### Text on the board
tPlace: side A | side A | side A | side A | side A | side A | side A | side A | DC 6-12v | CubePanel v1.2 | 12/21/2009 | by Seeed Studio | side B | side B | side B | side B | side B | side B | side B | side B
bPlace: 1K | 1K | 1K | 1K | 15K | 10K | Bee | 10uF | 10uF | TO220 | Vin | Vin | GND | GND
Milling: slot hole no plat | slot hole no plat | slot hole no plat | slot hole no plat | 3 slot drills with plat | slot hole no plat | slot hole no plat | slot hole no plat | slot hole no plat
Reference: 1 | 1 | VCC | 4 | BLUE | 1 | 8 | 1 | GREEN | 8 | RED | 5 | VCC | 8 | 8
